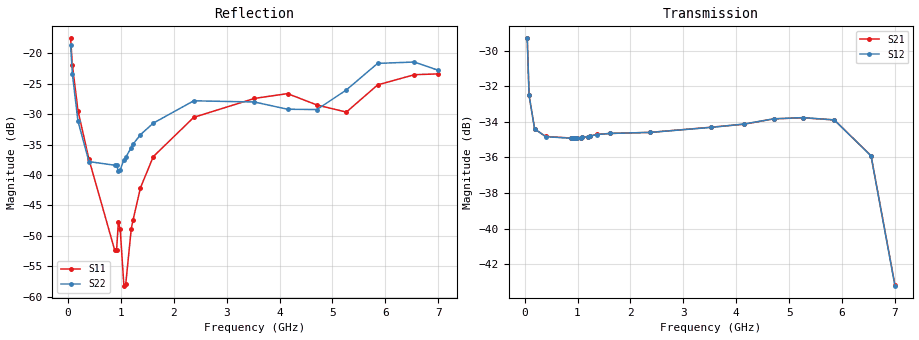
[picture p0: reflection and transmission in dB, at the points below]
! Integrated Device Technology
! Corporate Headquarters
! 6024 Silver Creek Valley Road
! San Jose, CA 95138  USA
! Phone:  1-408-284-8200
! Toll Free:  1-800-223-1366
! Webpage:  http://www.idt.com/
! Timing and RF Division
! 515 Groton Road, Suite 102
! Westford, MA 01886-6024
! Device:  F2258
! Description: Voltage Variable RF Attenuator
! Frequency:  50.0 -  6000.00 MHz
! Package:  3x3 mm Thin QFN Plastic Package: 16 pin
! Ports:  2 RF, 2 DC
!  Pin  1  = NC
!  Pin  2  = NC
!  Pin  3  = RF2  = Port 2
!  Pin  4  = GND
!  Pin  5  = Vdd
!  Pin  6  = NC
!  Pin  7  = VCTRL
!  Pin  8  = NC
!  Pin  9  = GND
!  Pin 10  = RF1  = Port 1
!  Pin 11  = NC
!  Pin 12  = NC
!  Pin 13  = NC
!  Pin 14  = NC
!  Pin 15  = NC
!  Pin 16  = NC
! Vcntrl:  1.980 Volts
! Vdd:  +3.300 Volts
! Current:  1.153 mA
! Data:  The device was measured on a the F2258 evaluation board which has
!  individual transmission lines to the RF pins.  Data was collected
!  using a calibrated network analyzer.  The evaluation board was
!  de-embedded using a TRL calibration technique.
!  The reference plane is the edge of the package pin.
! Misc:  SN 10
!  Action Tracker AT0285
! Date Measured:  2014-12-10
! Date:  2016-01-13  MJV
! Note:
!  Integrated Device Technology supplies this data as a sample of measured
!  data at the package pin for this product.  Your particular data for this
!  product may vary.
!  Data was taken at 25 degrees C.
!  Integrated Device Technology reserves the right to change this data at anytime.
!Freq_(GHz)  S11M_(dB)  S11P_(deg)  S21M_(dB)  S21P_(deg)  S12M_(dB)  S12P_(deg)  S22M_(dB)  S22P_(deg)
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# GHz S dB R 50
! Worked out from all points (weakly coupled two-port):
!   201 points, 50 MHz to 7 GHz, reference 50 ohm
!   highest |S21| = -29.31 dB at 50 MHz (marker M1); lowest = -43.2 dB at 7 GHz (marker M2)
!   lowest |S11| = -58.2 dB at 1.058 GHz (marker M3), VSWR 1.00, Z = 49.9 + j0.0559 ohm
!   |S11| at or under -10 dB: start of sweep to end of sweep
!   |S22| runs from -39.4 to -18.6 dB; largest |S21 - S12| = 7e-05
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0.05  -17.55 -110.9  -29.31 -66.3  -29.31 -66.3  -18.58 -107.5
0.08475  -21.97 -107.3  -32.51 -46.9  -32.51 -46.9  -23.46 -97.7
0.189  -29.41 -109.2  -34.39 -23.8  -34.39 -23.8  -31.12 -80.8
0.3975  -37.44 -119.0  -34.82 -13.0  -34.83 -13.0  -37.81 -42.2
0.884  -52.36 167.2  -34.91 -8.7  -34.92 -8.7  -38.40 13.1
0.91875  -52.41 149.7  -34.91 -8.6  -34.91 -8.6  -38.32 14.7
0.9535  -47.73 -162.0  -34.91 -8.6  -34.92 -8.5  -39.41 30.3
0.98825  -48.94 -173.6  -34.90 -8.5  -34.90 -8.5  -39.14 27.6
1.05775  -58.20 152.9  -34.88 -8.4  -34.89 -8.4  -37.49 26.2
1.0925  -57.93 118.5  -34.86 -8.3  -34.87 -8.3  -37.10 26.2
1.19675  -48.84 55.7  -34.83 -8.5  -34.83 -8.5  -35.50 24.7
1.2315  -47.38 45.8  -34.80 -8.5  -34.80 -8.4  -34.94 23.4
1.3705  -42.12 36.3  -34.70 -9.0  -34.71 -9.0  -33.38 22.8
1.61375  -36.98 32.5  -34.65 -10.3  -34.65 -10.3  -31.48 20.3
2.37825  -30.53 47.9  -34.59 -14.2  -34.59 -14.2  -27.81 22.3
3.525  -27.42 91.6  -34.30 -21.0  -34.31 -21.0  -28.01 48.8
4.1505  -26.63 104.9  -34.13 -25.6  -34.12 -25.6  -29.20 58.8
4.7065  -28.50 95.6  -33.83 -30.3  -33.83 -30.3  -29.25 40.1
5.2625  -29.67 54.1  -33.77 -36.4  -33.76 -36.4  -26.03 5.0
5.85325  -25.20 29.7  -33.89 -46.8  -33.89 -46.8  -21.66 -12.3
6.54825  -23.52 45.0  -35.90 -66.7  -35.91 -66.7  -21.44 -45.6
7  -23.39 84.4  -43.16 -62.9  -43.20 -62.4  -22.80 -127.5
